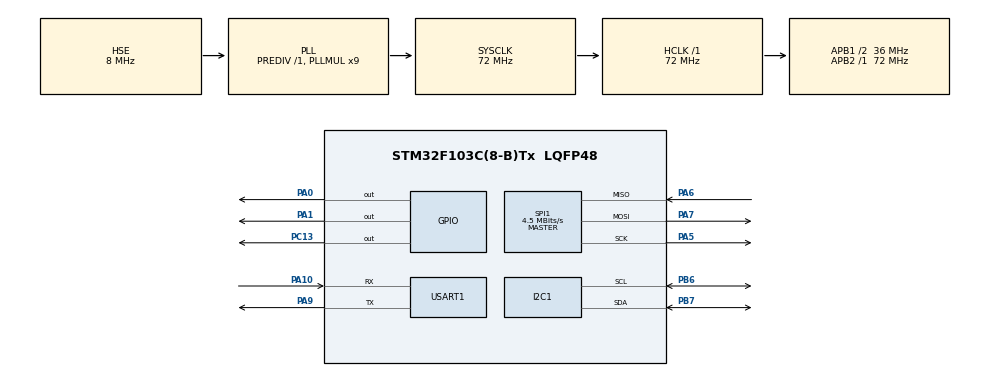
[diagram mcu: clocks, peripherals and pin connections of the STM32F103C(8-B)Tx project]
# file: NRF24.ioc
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Mcu.Family=STM32F1
Mcu.Name=STM32F103C(8-B)Tx
Mcu.Package=LQFP48
NVIC.PriorityGroup=NVIC_PRIORITYGROUP_4
PA0-WKUP.Signal=GPIO_Output
PA1.Signal=GPIO_Output
PA10.Mode=Asynchronous
PA10.Signal=USART1_RX
PA13.Mode=Serial_Wire
PA13.Signal=SYS_JTMS-SWDIO
PA14.Mode=Serial_Wire
PA14.Signal=SYS_JTCK-SWCLK
PA5.Mode=Full_Duplex_Master
PA5.Signal=SPI1_SCK
PA6.Mode=Full_Duplex_Master
PA6.Signal=SPI1_MISO
PA7.Mode=Full_Duplex_Master
PA7.Signal=SPI1_MOSI
PA9.Mode=Asynchronous
PA9.Signal=USART1_TX
PB6.Mode=I2C
PB6.Signal=I2C1_SCL
PB7.Mode=I2C
PB7.Signal=I2C1_SDA
PC13-TAMPER-RTC.Signal=GPIO_Output
PD0-OSC_IN.Mode=HSE-External-Oscillator
PD0-OSC_IN.Signal=RCC_OSC_IN
PD1-OSC_OUT.Mode=HSE-External-Oscillator
PD1-OSC_OUT.Signal=RCC_OSC_OUT
ProjectManager.HeapSize=0x200
ProjectManager.StackSize=0x400
ProjectManager.TargetToolchain=STM32CubeIDE
RCC.AHBFreq_Value=72000000
RCC.APB1CLKDivider=RCC_HCLK_DIV2
RCC.APB1Freq_Value=36000000
RCC.APB1TimFreq_Value=72000000
RCC.APB2Freq_Value=72000000
RCC.APB2TimFreq_Value=72000000
RCC.HCLKFreq_Value=72000000
RCC.PLLMUL=RCC_PLL_MUL9
RCC.PLLSourceVirtual=RCC_PLLSOURCE_HSE
RCC.SYSCLKFreq_VALUE=72000000
RCC.SYSCLKSource=RCC_SYSCLKSOURCE_PLLCLK
RCC.USBFreq_Value=72000000
SPI1.BaudRatePrescaler=SPI_BAUDRATEPRESCALER_16
SPI1.CalculateBaudRate=4.5 MBits/s
SPI1.Direction=SPI_DIRECTION_2LINES
SPI1.Mode=SPI_MODE_MASTER
SPI1.VirtualType=VM_MASTER
USART1.VirtualMode=VM_ASYNC
board=custom

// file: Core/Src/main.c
/* USER CODE BEGIN Header */
/**
  ******************************************************************************
  * @file           : main.c
  * @brief          : Main program body
  ******************************************************************************
  * @attention
  *
  * Copyright (c) 2026 STMicroelectronics.
  * All rights reserved.
  *
  * This software is licensed under terms that can be found in the LICENSE file
  * in the root directory of this software component.
  * If no LICENSE file comes with this software, it is provided AS-IS.
  *
  ******************************************************************************
  */

// personal comments

/* USER CODE END Header */
// headers for CubeMX configurations & standard C library for printf function
#include "main.h"
#include <stdio.h>

// Handles (handles are used to know which wiring block in the chips to control for communication)
I2C_HandleTypeDef hi2c1;
SPI_HandleTypeDef hspi1;
UART_HandleTypeDef huart1;

/* USER CODE BEGIN PV */

// Macros for driving the nRF24 control pins
// These macros are text replacements for setting the CE and CSN pins to high and low
// replacing the long statement with a much smaller one
#define NRF24_CE_HIGH()  HAL_GPIO_WritePin(GPIOA, GPIO_PIN_3, GPIO_PIN_SET)
#define NRF24_CE_LOW()   HAL_GPIO_WritePin(GPIOA, GPIO_PIN_3, GPIO_PIN_RESET)
#define NRF24_CSN_HIGH() HAL_GPIO_WritePin(GPIOA, GPIO_PIN_4, GPIO_PIN_SET)
#define NRF24_CSN_LOW()  HAL_GPIO_WritePin(GPIOA, GPIO_PIN_4, GPIO_PIN_RESET)

// Custom data frame structure supporting full telemetry (12 bytes total)
typedef struct __attribute__((packed)) {
    uint32_t sample_id;
    float temperature;
    float humidity;
} SensorPayload;

SensorPayload my_data;
uint32_t loop_counter = 0;

// Hardware handle generated by CubeMX for the I2C setup
extern I2C_HandleTypeDef hi2c1;
#define AHT_I2C_ADDR (0x38 << 1) // 7-bit standard address (fixed factory number)
// 0x38 shifted for HAL write formatting (the final bit is used for the read/write flag bit)

/* USER CODE END PV */

void SystemClock_Config(void);
static void MX_GPIO_Init(void);
static void MX_SPI1_Init(void);
static void MX_USART1_UART_Init(void);
static void MX_I2C1_Init(void);

/* USER CODE BEGIN 0 */

// 1. Intercept printf and push characters out of USART1 hardware
#ifdef __GNUC__
#define PUTCHAR_PROTOTYPE int __io_putchar(int ch)
#else
#define PUTCHAR_PROTOTYPE int fputc(int ch, FILE *f)
#endif

// take all char from printf and output to computer screen (no chip screen)
PUTCHAR_PROTOTYPE
{
  HAL_UART_Transmit(&huart1, (uint8_t *)&ch, 1, HAL_MAX_DELAY);
  return ch;
}

// wake and calibrate the temp sensor
void AHT_Init(void) {
    uint8_t init_cmd[] = {0xBE, 0x08, 0x00};
    HAL_Delay(40); // Wait for sensor startup power stabilization
    // send the initiation bytes to the sensors address, declare a length of 3 bytes
    // and wait until it finishes sending
    HAL_I2C_Master_Transmit(&hi2c1, AHT_I2C_ADDR, init_cmd, 3, HAL_MAX_DELAY);
    HAL_Delay(20);
}

// read sensor values (pass the temp and humidity as pointers so they can be edited in the function)
void AHT_Read(float *temperature, float *humidity) {
    uint8_t read_cmd[] = {0xAC, 0x33, 0x00};
    uint8_t raw_buffer[6];
    HAL_StatusTypeDef status;

    // Trigger measurement
    status = HAL_I2C_Master_Transmit(&hi2c1, AHT_I2C_ADDR, read_cmd, 3, HAL_MAX_DELAY);
    if (status != HAL_OK) {
        printf("[I2C Error] Transmit failed! Code: %d\r\n", status);
        return;
    }

    HAL_Delay(80);

    // Receive data
    status = HAL_I2C_Master_Receive(&hi2c1, AHT_I2C_ADDR, raw_buffer, 6, HAL_MAX_DELAY);
    if (status == HAL_OK) {
    	// << >> bit shifting, & masking use dto fix the 20bit number into single int
        uint32_t raw_humidity = (((uint32_t)raw_buffer[1] << 12) | ((uint32_t)raw_buffer[2] << 4) | ((uint32_t)raw_buffer[3] >> 4)) & 0xFFFFF;
        uint32_t raw_temperature = (((uint32_t)(raw_buffer[3] & 0x0F) << 16) | ((uint32_t)raw_buffer[4] << 8) | (uint32_t)raw_buffer[5]) & 0xFFFFF;

        *humidity = ((float)raw_humidity / 1048576.0f) * 100.0f;
        *temperature = ((float)raw_temperature / 1048576.0f) * 200.0f - 50.0f;
    } else {
        printf("[I2C Error] Receive failed! Code: %d\r\n", status);
    }
}

// 2. Low-level routine to write data to an nRF24 register address
void NRF24_WriteRegister(uint8_t reg, uint8_t value) {
    uint8_t buf[2];
    // Clear upper bits and cleanly add the Write Command mask (0x20)
    buf[0] = (reg & 0x1F) | 0x20;
    buf[1] = value;

    NRF24_CSN_LOW();
    HAL_SPI_Transmit(&hspi1, buf, 2, HAL_MAX_DELAY);
    NRF24_CSN_HIGH();
}

// write several bytes to radio
void NRF24_WriteRegisterBuf(uint8_t reg, uint8_t *buf, uint8_t len) {
    uint8_t cmd = (reg & 0x1F) | 0x20;
    NRF24_CSN_LOW();
    HAL_SPI_Transmit(&hspi1, &cmd, 1, HAL_MAX_DELAY);
    HAL_SPI_Transmit(&hspi1, buf, len, HAL_MAX_DELAY);
    NRF24_CSN_HIGH();
}

// clear outbound bin of any stuck packets
void NRF24_FlushTX(void) {
    uint8_t cmd = 0xE1; // FLUSH_TX command
    NRF24_CSN_LOW();
    HAL_SPI_Transmit(&hspi1, &cmd, 1, HAL_MAX_DELAY);
    NRF24_CSN_HIGH();
}

uint8_t NRF24_ReadRegister(uint8_t reg) {
    uint8_t cmd = reg & 0x1F;
    uint8_t val = 0;
    uint8_t dummy = 0xFF; // Safe padding byte

    NRF24_CSN_LOW();
    // 1. Send the read register command
    HAL_SPI_Transmit(&hspi1, &cmd, 1, HAL_MAX_DELAY);
    // 2. Transmit dummy data while simultaneously capturing the returning register content
    HAL_SPI_TransmitReceive(&hspi1, &dummy, &val, 1, HAL_MAX_DELAY);
    NRF24_CSN_HIGH();

    return val;
}

// 3. Basic radio configuration sequence for a simple broadcast pipeline
void NRF24_Init(void) {
    // 1. Give the electrical power rail time to settle from 0V
    HAL_Delay(100);

    // 2. Drive SPI lines into a stable idle state immediately
    NRF24_CE_LOW();
    NRF24_CSN_HIGH();
    HAL_Delay(10);

    // 3. Force a complete chip Power Down to wipe its state machine
    // (Writing 0x00 turns off PWR_UP entirely)
    NRF24_WriteRegister(0x00, 0x00);
    HAL_Delay(20); // Wait for the crystal oscillator to shut off completely

    // 4. Run your regular configuration parameters now that it's clean
    NRF24_WriteRegister(0x00, 0x0E); // Power back up, Transmit Mode, 2-byte CRC
    NRF24_WriteRegister(0x01, 0x00); // Disable Auto-ACK
    NRF24_WriteRegister(0x05, 0x4C); // Channel 76
    NRF24_WriteRegister(0x06, 0x06); // 1 Mbps, 0 dBm

    //uint8_t address[5] = {0x12, 0x34, 0x56, 0x78, 0x9A}; // device A
    //uint8_t address[5] = {0x76, 0x98, 0xBA, 0xDC, 0xFE}; // device B
    uint8_t address[5] = {0x55, 0x98, 0xBA, 0xDC, 0xFE}; // device C
    NRF24_WriteRegisterBuf(0x10, address, 5); // TX_ADDR

    HAL_Delay(10); // Give the radio a brief moment to stabilize into Standby-I mode
}

// 4. Transmits a raw structured block of memory across the airwaves
void NRF24_TransmitPacket(uint8_t *payload, uint8_t size) {
    uint8_t cmd = 0xA0;

    // Reset status flags and flush the pipeline cleanly
    NRF24_WriteRegister(0x07, 0x70);
    NRF24_FlushTX();

    // Load payload over SPI
    NRF24_CSN_LOW();
    HAL_SPI_Transmit(&hspi1, &cmd, 1, HAL_MAX_DELAY);
    HAL_SPI_Transmit(&hspi1, payload, size, HAL_MAX_DELAY);
    NRF24_CSN_HIGH();

    // 🚀 Pulse CE to fire the transmitter
    NRF24_CE_HIGH();
    HAL_Delay(1); // 1ms is plenty of time for 12 bytes to air out
    NRF24_CE_LOW();  // Return to standby mode so the TX_DS flag settles

    // Now safely read the status register using the new full-duplex function
    uint8_t status = NRF24_ReadRegister(0x07);
    printf("[Radio Status] Reg 0x07: 0x%02X\r\n", status);
}

/* USER CODE END 0 */

int main(void)
{

  /* MCU Configuration--------------------------------------------------------*/

  /* Reset of all peripherals, Initializes the Flash interface and the Systick. */
  HAL_Init();

  /* Configure the system clock */
  SystemClock_Config();

  /* Initialize all configured peripherals */
  MX_GPIO_Init();
  MX_SPI1_Init();
  MX_USART1_UART_Init();
  MX_I2C1_Init();
  /* USER CODE BEGIN 2 */

  NRF24_Init();
  AHT_Init(); // Fire up I2C calibrations
  uint8_t channel = NRF24_ReadRegister(0x05);
  printf("nRF24 SPI Test - Channel Register reads: 0x%02X (Expected: 0x4C)\r\n", channel);

  printf("--- System Online: Broadcasting Telemetry ---\r\n");

  /* USER CODE END 2 */

  /* Infinite loop */
  /* USER CODE BEGIN WHILE */
  while (1)
    {
          float live_temp = 0.0f;
          float live_hum = 0.0f;

          // 1. Fetch real physical data points from our I2C wires
          AHT_Read(&live_temp, &live_hum);

          // 2. Wrap those metrics into our structural data pipeline framework
          my_data.sample_id = ++loop_counter;
          my_data.temperature = live_temp;
          my_data.humidity = live_hum;

          // 3. Status Print to USART1 local debugging console
          printf("[STM32 Node] ID: %lu | Temp: %.2f C | Hum: %.2f %%\r\n",
                 my_data.sample_id, my_data.temperature, my_data.humidity);

//          NRF24_Init();
          // 4. Send the updated 12-byte packed framework out across the airwaves
          NRF24_TransmitPacket((uint8_t*)&my_data, sizeof(my_data));

          uint8_t fifo_status = NRF24_ReadRegister(0x17);
          printf("[FIFO Status] Reg 0x17: 0x%02X\r\n", fifo_status);
          uint8_t config_reg = NRF24_ReadRegister(0x00);
          printf("[CONFIG Check] Reg 0x00: 0x%02X\r\n", config_reg);

          // Success Double-Blink routine indicators
          HAL_GPIO_WritePin(GPIOC, GPIO_PIN_13, GPIO_PIN_RESET);
          HAL_Delay(80);
          HAL_GPIO_WritePin(GPIOC, GPIO_PIN_13, GPIO_PIN_SET);
          HAL_Delay(80);
          HAL_GPIO_WritePin(GPIOC, GPIO_PIN_13, GPIO_PIN_RESET);
          HAL_Delay(80);
          HAL_GPIO_WritePin(GPIOC, GPIO_PIN_13, GPIO_PIN_SET);

          HAL_Delay(760);

    /* USER CODE END WHILE */

  }
}

void SystemClock_Config(void)
{
  RCC_OscInitTypeDef RCC_OscInitStruct = {0};
  RCC_ClkInitTypeDef RCC_ClkInitStruct = {0};

  /** Initializes the RCC Oscillators according to the specified parameters
  * in the RCC_OscInitTypeDef structure.
  */
  RCC_OscInitStruct.OscillatorType = RCC_OSCILLATORTYPE_HSE;
  RCC_OscInitStruct.HSEState = RCC_HSE_ON;
  RCC_OscInitStruct.HSEPredivValue = RCC_HSE_PREDIV_DIV1;
  RCC_OscInitStruct.HSIState = RCC_HSI_ON;
  RCC_OscInitStruct.PLL.PLLState = RCC_PLL_ON;
  RCC_OscInitStruct.PLL.PLLSource = RCC_PLLSOURCE_HSE;
  RCC_OscInitStruct.PLL.PLLMUL = RCC_PLL_MUL9;
  if (HAL_RCC_OscConfig(&RCC_OscInitStruct) != HAL_OK)
  {
    Error_Handler();
  }

  /** Initializes the CPU, AHB and APB buses clocks
  */
  RCC_ClkInitStruct.ClockType = RCC_CLOCKTYPE_HCLK|RCC_CLOCKTYPE_SYSCLK
                              |RCC_CLOCKTYPE_PCLK1|RCC_CLOCKTYPE_PCLK2;
  RCC_ClkInitStruct.SYSCLKSource = RCC_SYSCLKSOURCE_PLLCLK;
  RCC_ClkInitStruct.AHBCLKDivider = RCC_SYSCLK_DIV1;
  RCC_ClkInitStruct.APB1CLKDivider = RCC_HCLK_DIV2;
  RCC_ClkInitStruct.APB2CLKDivider = RCC_HCLK_DIV1;

  if (HAL_RCC_ClockConfig(&RCC_ClkInitStruct, FLASH_LATENCY_2) != HAL_OK)
  {
    Error_Handler();
  }
}

static void MX_I2C1_Init(void)
{

  hi2c1.Instance = I2C1;
  hi2c1.Init.ClockSpeed = 100000;
  hi2c1.Init.DutyCycle = I2C_DUTYCYCLE_2;
  hi2c1.Init.OwnAddress1 = 0;
  hi2c1.Init.AddressingMode = I2C_ADDRESSINGMODE_7BIT;
  hi2c1.Init.DualAddressMode = I2C_DUALADDRESS_DISABLE;
  hi2c1.Init.OwnAddress2 = 0;
  hi2c1.Init.GeneralCallMode = I2C_GENERALCALL_DISABLE;
  hi2c1.Init.NoStretchMode = I2C_NOSTRETCH_DISABLE;
  if (HAL_I2C_Init(&hi2c1) != HAL_OK)
  {
    Error_Handler();
  }

}

static void MX_SPI1_Init(void)
{

  /* SPI1 parameter configuration*/
  hspi1.Instance = SPI1;
  hspi1.Init.Mode = SPI_MODE_MASTER;
  hspi1.Init.Direction = SPI_DIRECTION_2LINES;
  hspi1.Init.DataSize = SPI_DATASIZE_8BIT;
  hspi1.Init.CLKPolarity = SPI_POLARITY_LOW;
  hspi1.Init.CLKPhase = SPI_PHASE_1EDGE;
  hspi1.Init.NSS = SPI_NSS_SOFT;
  hspi1.Init.BaudRatePrescaler = SPI_BAUDRATEPRESCALER_16;
  hspi1.Init.FirstBit = SPI_FIRSTBIT_MSB;
  hspi1.Init.TIMode = SPI_TIMODE_DISABLE;
  hspi1.Init.CRCCalculation = SPI_CRCCALCULATION_DISABLE;
  hspi1.Init.CRCPolynomial = 10;
  if (HAL_SPI_Init(&hspi1) != HAL_OK)
  {
    Error_Handler();
  }

}

static void MX_USART1_UART_Init(void)
{

  huart1.Instance = USART1;
  huart1.Init.BaudRate = 115200;
  huart1.Init.WordLength = UART_WORDLENGTH_8B;
  huart1.Init.StopBits = UART_STOPBITS_1;
  huart1.Init.Parity = UART_PARITY_NONE;
  huart1.Init.Mode = UART_MODE_TX_RX;
  huart1.Init.HwFlowCtl = UART_HWCONTROL_NONE;
  huart1.Init.OverSampling = UART_OVERSAMPLING_16;
  if (HAL_UART_Init(&huart1) != HAL_OK)
  {
    Error_Handler();
  }

}

static void MX_GPIO_Init(void)
{
  GPIO_InitTypeDef GPIO_InitStruct = {0};

  /* GPIO Ports Clock Enable */
  __HAL_RCC_GPIOC_CLK_ENABLE();
  __HAL_RCC_GPIOD_CLK_ENABLE();
  __HAL_RCC_GPIOA_CLK_ENABLE();
  __HAL_RCC_GPIOB_CLK_ENABLE();

  /*Configure GPIO pin Output Level */
  HAL_GPIO_WritePin(GPIOC, GPIO_PIN_13, GPIO_PIN_RESET);

  /*Configure GPIO pin Output Level */
  HAL_GPIO_WritePin(GPIOA, GPIO_PIN_3|GPIO_PIN_4, GPIO_PIN_RESET);

  /*Configure GPIO pin : PC13 */
  GPIO_InitStruct.Pin = GPIO_PIN_13;
  GPIO_InitStruct.Mode = GPIO_MODE_OUTPUT_PP;
  GPIO_InitStruct.Pull = GPIO_NOPULL;
  GPIO_InitStruct.Speed = GPIO_SPEED_FREQ_LOW;
  HAL_GPIO_Init(GPIOC, &GPIO_InitStruct);

  /*Configure GPIO pins : PA3 PA4 */
  GPIO_InitStruct.Pin = GPIO_PIN_3|GPIO_PIN_4;
  GPIO_InitStruct.Mode = GPIO_MODE_OUTPUT_PP;
  GPIO_InitStruct.Pull = GPIO_NOPULL;
  GPIO_InitStruct.Speed = GPIO_SPEED_FREQ_LOW;
  HAL_GPIO_Init(GPIOA, &GPIO_InitStruct);

}

void Error_Handler(void)
{
  __disable_irq();
  while (1)
  {
  }
}
